VERSION 5.7 ;
  NOWIREEXTENSIONATPIN ON ;
  DIVIDERCHAR "/" ;
  BUSBITCHARS "[]" ;
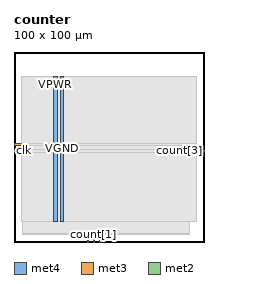
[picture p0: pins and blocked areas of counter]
MACRO counter
  CLASS BLOCK ;
  FOREIGN counter ;
  ORIGIN 0.000 0.000 ;
  SIZE 100.000 BY 100.000 ;
  PIN VGND
    DIRECTION INOUT ;
    USE GROUND ;
    PORT
      LAYER met4 ;
        RECT 24.340 10.640 25.940 87.280 ;
    END
  END VGND
  PIN VPWR
    DIRECTION INOUT ;
    USE POWER ;
    PORT
      LAYER met4 ;
        RECT 21.040 10.640 22.640 87.280 ;
    END
  END VPWR
  PIN clk
    DIRECTION INPUT ;
    USE SIGNAL ;
    ANTENNAGATEAREA 0.852000 ;
    PORT
      LAYER met3 ;
        RECT 0.000 47.640 4.000 48.240 ;
    END
  END clk
  PIN count[0]
    DIRECTION OUTPUT ;
    USE SIGNAL ;
    ANTENNADIFFAREA 0.445500 ;
    PORT
      LAYER met2 ;
        RECT 38.730 0.000 39.010 4.000 ;
    END
  END count[0]
  PIN count[1]
    DIRECTION OUTPUT ;
    USE SIGNAL ;
    ANTENNADIFFAREA 0.445500 ;
    PORT
      LAYER met2 ;
        RECT 41.950 0.000 42.230 4.000 ;
    END
  END count[1]
  PIN count[2]
    DIRECTION OUTPUT ;
    USE SIGNAL ;
    ANTENNADIFFAREA 0.445500 ;
    PORT
      LAYER met3 ;
        RECT 0.000 51.040 4.000 51.640 ;
    END
  END count[2]
  PIN count[3]
    DIRECTION OUTPUT ;
    USE SIGNAL ;
    ANTENNADIFFAREA 0.445500 ;
    PORT
      LAYER met3 ;
        RECT 96.000 47.640 100.000 48.240 ;
    END
  END count[3]
  PIN rst
    DIRECTION INPUT ;
    USE SIGNAL ;
    ANTENNAGATEAREA 0.196500 ;
    PORT
      LAYER met2 ;
        RECT 45.170 0.000 45.450 4.000 ;
    END
  END rst
  OBS
      LAYER nwell ;
        RECT 5.330 10.795 94.490 87.125 ;
      LAYER li1 ;
        RECT 5.520 10.795 94.300 87.125 ;
      LAYER met1 ;
        RECT 4.210 10.640 94.300 87.280 ;
      LAYER met2 ;
        RECT 4.230 4.280 92.370 87.225 ;
        RECT 4.230 4.000 38.450 4.280 ;
        RECT 39.290 4.000 41.670 4.280 ;
        RECT 42.510 4.000 44.890 4.280 ;
        RECT 45.730 4.000 92.370 4.280 ;
      LAYER met3 ;
        RECT 3.990 52.040 96.000 87.205 ;
        RECT 4.400 50.640 96.000 52.040 ;
        RECT 3.990 48.640 96.000 50.640 ;
        RECT 4.400 47.240 95.600 48.640 ;
        RECT 3.990 10.715 96.000 47.240 ;
  END
END counter
END LIBRARY

